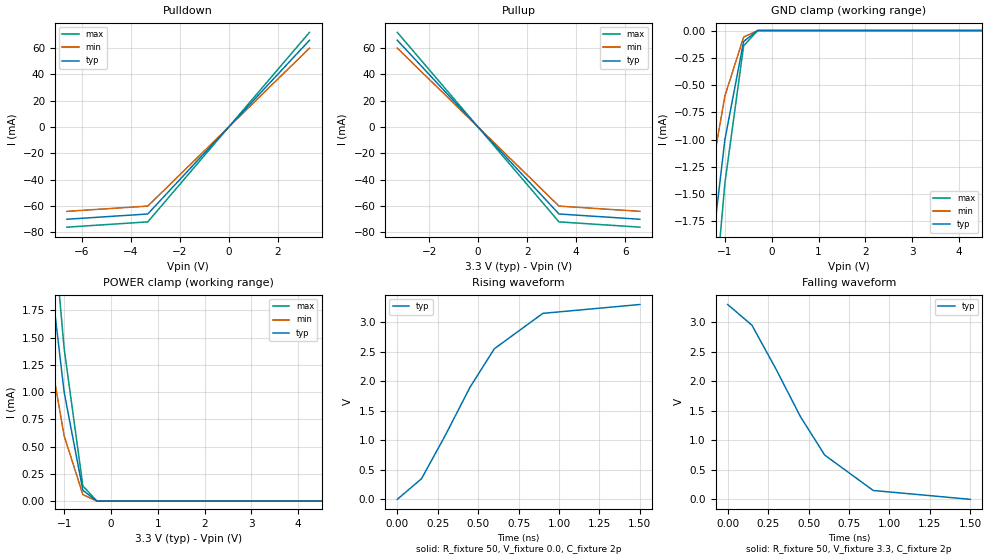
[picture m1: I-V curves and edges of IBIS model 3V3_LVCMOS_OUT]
| easyeda-ngspice-sim v2.3 regression fixture -- TEST DOUBLE, NOT VENDOR DATA
| 这是仓库自写的简化 IBIS，用于验证解析器与行为级转换逻辑。
| 数值是工程上合理的量级，不代表任何真实器件。
[IBIS Ver]   4.2
[File Name]   fixture_lvcmos.ibs
[File Rev]   1.0
[Date]   2026-11-01
[Source]   hand written test double
[Component]   FIXTURE_FPGA
[Manufacturer]   easyeda-ngspice-sim
[Package]
|   R_pkg   L_pkg   C_pkg
   0.12   1.8n   0.9p
[Pin]  signal_name   model_name   R_pin   L_pin   C_pin
89   CLKIN   3V3_LVCMOS_IN   0.05   1.2n   0.6p
45   DATA_OUT   3V3_LVCMOS_OUT   0.08   2.0n   0.8p
12   VCC   POWER
13   GND   GND
60   DCLK_P   3V3_LVDS_OUT
61   DCLK_N   3V3_LVDS_OUT
62   DRX_P   3V3_LVDS_IN
63   DRX_N   3V3_LVDS_IN
| keep the pairwise relationship explicit (IBIS [Diff Pin])
[Diff Pin]  inv_pin   vdiff   tdelay_typ  tdelay_min  tdelay_max
60  61  0.30V   NA  NA  NA
62  63  0.20V   NA  NA  NA
[Model]   3V3_LVCMOS_IN
Model_type   Input
C_comp   4.0pF   3.5pF   4.5pF
Vinl   0.8V
Vinh   2.0V
Vmeas   1.65V
[Model]   3V3_LVDS_OUT
Model_type   Output_diff
C_comp   1.8pF   1.6pF   2.0pF
Vmeas   1.2V
[Model]   3V3_LVDS_IN
Model_type   Input_diff
C_comp   2.2pF   2.0pF   2.4pF
Vinl   0.10V
Vinh   0.15V
| Models and submodels in the file (4): 3V3_LVCMOS_IN (Input), 3V3_LVDS_OUT (Output_diff), 3V3_LVDS_IN (Input_diff), 3V3_LVCMOS_OUT (Output)
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[Model]   3V3_LVCMOS_OUT
Model_type   Output
C_comp   3.0pF   2.6pF   3.4pF
Vmeas   1.65V
| v2.5.1：显式给出参考电压（IBIS 里这是 [Model] 级子参数）。
| [POWER Clamp] 用它作 Vcc；缺了它 POWER clamp 的自变量无法确定。
[Voltage Range]   3.3V   3.0V   3.6V
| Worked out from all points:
|   slope of the pulldown table from 0 to 0.495 V, typ, clamps not added: 50 ohm
|   slope of the pullup table from 0 to 0.495 V, typ, clamps not added: 50 ohm
|   rising waveform, R_fixture 50, V_fixture 0.0, C_fixture 2p: 20-80 % time 433ps typ, NA min, NA max; typ from 0 V to 3.3 V
|   falling waveform, R_fixture 50, V_fixture 3.3, C_fixture 2p: 20-80 % time 433ps typ, NA min, NA max; typ from 3.3 V to 0 V
| 【IBIS 4.0 语义】[Pullup] 的自变量是 Vtable = Vcc - Voutput。
| 下面这条是 50Ω 上管：Vtable=1.65V（即 Vout=1.65V）时 -33mA。
[Pullup]
|   Voltage   I(typ)   I(min)   I(max)
-3.3V     66mA       60mA       72mA
0V        0A         0A         0A
1.65V     -33mA      -30mA      -36mA
3.3V      -66mA      -60mA      -72mA
6.6V      -70mA      -64mA      -76mA
| 【IBIS 4.0 语义】[Pulldown] 是 ground-relative（Vtable = Voutput - GND）。
[Pulldown]
|   Voltage   I(typ)   I(min)   I(max)
-6.6V     -70mA      -64mA      -76mA
-3.3V     -66mA      -60mA      -72mA
-1.65V    -33mA      -30mA      -36mA
0V        0A         0A         0A
1.65V     33mA       30mA       36mA
3.3V      66mA       60mA       72mA
[Ramp]
| variable   dV/dt(typ)   dV/dt(min)   dV/dt(max)
dv/dt_r   1.2V/0.35n   0.9V/0.55n   1.5V/0.25n
dv/dt_f   1.2V/0.32n   0.9V/0.50n   1.5V/0.22n
| v2.5.1 重做的 clamp 表：严格按 IBIS 4.0 第 [Pulldown],[Pullup],
| [GND Clamp],[POWER Clamp] 节给出的形状与符号。
|   POWER clamp: Vtable = Vcc - Voutput，导通区 Vtable < 0，电流为**正**。
|   GND   clamp: Vtable = Voutput - GND，导通区 Vtable < 0，电流为**负**。
| 规范原文示例（5V 器件）：
|   [GND Clamp]   -5.0V -3900m / -0.7V -80m / -0.4V 0 / 5.0V 0
|   [POWER Clamp] -5.0V  4450m / -0.7V  95m / -0.4V 0 / 0.0V 0
| 这里按 3.3V 器件缩放，并保证单调（电流随电压不反向）。
[POWER Clamp]
| Vtable = Vcc - Voutput   (Vtable<0 => Voutput 高于 Vcc)
|   Voltage   I(typ)   I(min)   I(max)
-6.6V     95mA       70mA       120mA
-4V       12mA       8mA        16mA
-1V       1mA        600uA      1.4mA
-600mV    100uA      60uA       140uA
-300mV    0A         0A         0A
0V        0A         0A         0A
6.6V      0A         0A         0A
[GND Clamp]
| Vtable = Voutput - GND   (Vtable<0 => Voutput 低于 GND)
|   Voltage   I(typ)   I(min)   I(max)
-6.6V     -95mA      -70mA      -120mA
-4V       -12mA      -8mA       -16mA
-1V       -1mA       -600uA     -1.4mA
-600mV    -100uA     -60uA      -140uA
-300mV    0A         0A         0A
0V        0A         0A         0A
6.6V      0A         0A         0A
[Rising Waveform]
R_fixture = 50
V_fixture = 0.0
C_fixture = 2p
| Time   V(typ)   V(min)   V(max)
0s        0V         NA         NA
150ps     350mV      NA         NA
300ps     1.1V       NA         NA
450ps     1.9V       NA         NA
600ps     2.55V      NA         NA
900ps     3.15V      NA         NA
1.5ns     3.3V       NA         NA
[Falling Waveform]
R_fixture = 50
V_fixture = 3.3
C_fixture = 2p
| Time   V(typ)
0s        3.3V       NA         NA
150ps     2.95V      NA         NA
300ps     2.2V       NA         NA
450ps     1.4V       NA         NA
600ps     750mV      NA         NA
900ps     150mV      NA         NA
1.5ns     0V         NA         NA
